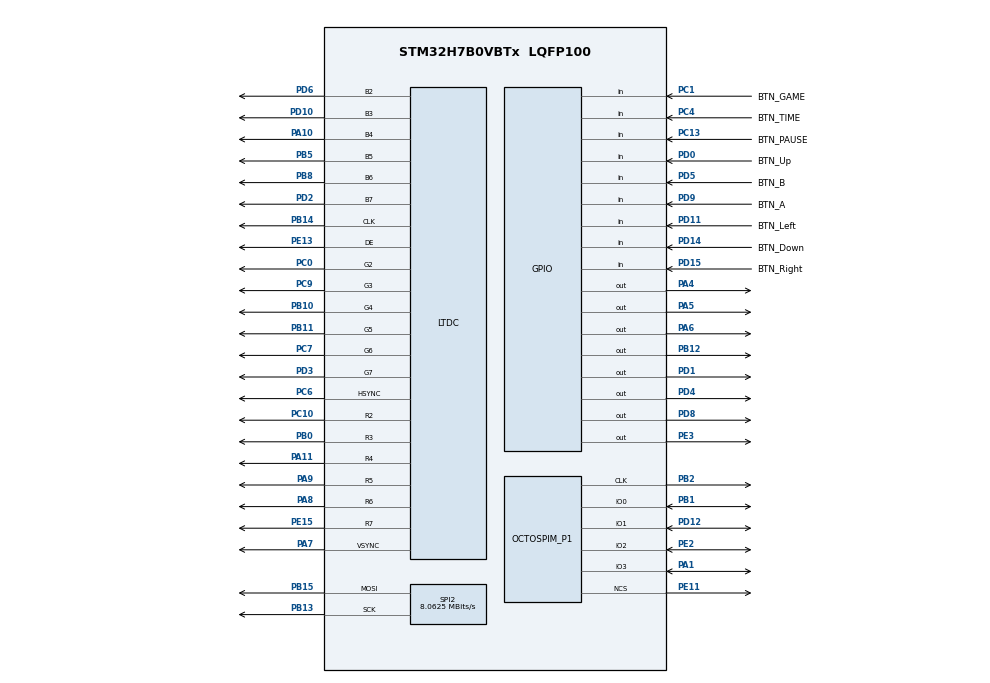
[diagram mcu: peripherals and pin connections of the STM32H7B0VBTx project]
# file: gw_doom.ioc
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SPI2.VirtualType=VM_MASTER
PB10.Mode=RGB666
PB13.Signal=SPI2_SCK
PA5.PinState=GPIO_PIN_SET
OCTOSPI1.ChipSelectBoundary=0
PE2.Mode=OCTOSPI1_IOL_Port1L
PD4.Signal=GPIO_Output
PC7.Signal=LTDC_G6
PB12.PinState=GPIO_PIN_SET
PD0.Signal=GPIO_Input
PD8.Signal=GPIO_Output
PB2.Signal=OCTOSPIM_P1_CLK
RCC.DIVM3=4
PC1.GPIO_PuPd=GPIO_PULLUP
VP_OCTOSPI1_VS_quad.Mode=quad_mode
LTDC.PixelFormat_L0=LTDC_PIXEL_FORMAT_RGB565
PC4.GPIO_Label=BTN_TIME
PB14.Mode=RGB666
PC9.Mode=RGB666
SPI2.CalculateBaudRate=8.0625 MBits/s
PE2.Signal=OCTOSPIM_P1_IO2
PA8.Signal=LTDC_R6
PD14.GPIO_PuPd=GPIO_PULLUP
PE13.Mode=RGB666
PD3.Mode=RGB666
LTDC.HSync=10
Mcu.Package=LQFP100
PB1.Signal=OCTOSPIM_P1_IO0
SPI2.Mode=SPI_MODE_MASTER
RCC.PLL3FRACN=0
PD12.Signal=OCTOSPIM_P1_IO1
PA10.Signal=LTDC_B4
LTDC.VSync=2
RCC.APB4Freq_Value=32000000
PB13.Mode=TX_Only_Simplex_Unidirect_Master
PD9.GPIO_PuPd=GPIO_PULLUP
PD15.Signal=GPIO_Input
PD9.GPIO_Label=BTN_A
PC13.Signal=GPIO_Input
PD3.Signal=LTDC_G7
PC6.Signal=LTDC_HSYNC
PD1.Signal=GPIO_Output
PA6.PinState=GPIO_PIN_SET
PC0.Signal=LTDC_G2
PD6.Mode=RGB666
LTDC.ImageWidth_L0=320
PD10.Signal=LTDC_B3
PD4.PinState=GPIO_PIN_SET
RCC.CDPPRE1=RCC_APB1_DIV2
RCC.CDPPRE2=RCC_APB2_DIV2
PB11.Mode=RGB666
PC6.Mode=RGB666
PA9.Signal=LTDC_R5
RCC.DIVN3=9
PB10.Signal=LTDC_G4
PB14.Signal=LTDC_CLK
PA5.Signal=GPIO_Output
PA1.Mode=OCTOSPI1_IOL_Port1L
PE15.Signal=LTDC_R7
RCC.CDPPRE=RCC_APB3_DIV2
OCTOSPI1.FifoThreshold=4
PA4.Signal=GPIO_Output
OCTOSPI1.MemoryType=HAL_OSPI_MEMTYPE_MACRONIX
PB5.Signal=LTDC_B5
PD12.Mode=OCTOSPI1_IOL_Port1L
PD11.Signal=GPIO_Input
PD1.PinState=GPIO_PIN_RESET
LTDC.Alpha_L0=50
PA11.Signal=LTDC_R4
ProjectManager.HeapSize=0x200
PB1.Mode=OCTOSPI1_IOL_Port1L
PD0.GPIO_PuPd=GPIO_PULLUP
NVIC.PriorityGroup=NVIC_PRIORITYGROUP_4
OCTOSPI1.FreeRunningClock=HAL_OSPI_FREERUNCLK_DISABLE
PB8.Mode=RGB666
PE3.Signal=GPIO_Output
PA8.Mode=RGB666
SPI2.DataSize=SPI_DATASIZE_8BIT
PD2.Signal=LTDC_B7
RCC.DIVR3=26
PB0.Signal=LTDC_R3
PC1.Signal=GPIO_Input
LTDC.Alpha0_L0=128
PE15.Mode=RGB666
Mcu.Family=STM32H7
RCC.CortexFreq_Value=64000000
OCTOSPI1.DeviceSize=20
LTDC.HBP=51
PC10.Signal=LTDC_R2
PD0.GPIO_Label=BTN_Up
PA11.Mode=RGB666
PC13.GPIO_Label=BTN_PAUSE
PB11.Signal=LTDC_G5
PB15.Signal=SPI2_MOSI
LTDC.PCPolarity=LTDC_PCPOLARITY_IIPC
ProjectManager.StackSize=0x400
PD11.GPIO_PuPd=GPIO_PULLUP
OCTOSPI1.ClockPrescaler=1
PE11.Mode=OCTOSPI1_Port1_NCS
RCC.HCLKFreq_Value=64000000
PD11.GPIO_Label=BTN_Left
LTDC.WindowX1_L0=320
PD10.Mode=RGB666
SPI2.BaudRatePrescaler=SPI_BAUDRATEPRESCALER_16
PE3.PinState=GPIO_PIN_SET
LTDC.VBP=6
PE13.Signal=LTDC_DE
OCTOSPI1.ChipSelectHighTime=2
PB5.Mode=RGB666
PC13.GPIO_PuPd=GPIO_PULLUP
LTDC.HFP=12
LTDC.ActiveW=320
RCC.APB3Freq_Value=32000000
PA6.Signal=GPIO_Output
PD5.GPIO_Label=BTN_B
PD15.GPIO_PuPd=GPIO_PULLUP
SPI2.Direction=SPI_DIRECTION_2LINES_TXONLY
PD6.Signal=LTDC_B2
RCC.SRDPPRE=RCC_APB4_DIV2
LTDC.FBStartAdress_L0=0x24000000
OCTOSPI1.ClockMode=HAL_OSPI_CLOCK_MODE_0
LTDC.VFP=8
PD15.GPIO_Label=BTN_Right
LTDC.WindowY1_L0=240
PA7.Mode=RGB666
PA10.Mode=RGB666
PC4.GPIO_PuPd=GPIO_PULLUP
SPI2.NSSPMode=SPI_NSS_PULSE_DISABLE
PC4.Signal=GPIO_Input
PC10.Mode=RGB666
PD9.Signal=GPIO_Input
PD5.Signal=GPIO_Input
PC0.Mode=RGB666
PA9.Mode=RGB666
PA4.PinState=GPIO_PIN_SET
ProjectManager.TargetToolchain=Makefile
LTDC.ActiveH=240
RCC.USBFreq_Value=129000000
PE11.Signal=OCTOSPIM_P1_NCS
PA1.Signal=OCTOSPIM_P1_IO3
PD2.Mode=RGB666
PB0.Mode=RGB666
board=custom
PB15.Mode=TX_Only_Simplex_Unidirect_Master
RCC.APB2Freq_Value=32000000
LTDC.Layers=0
RCC.ADCFreq_Value=129000000
PC1.GPIO_Label=BTN_GAME
PD5.GPIO_PuPd=GPIO_PULLUP
PD14.GPIO_Label=BTN_Down
Mcu.Name=STM32H7B0VBTx
NVIC.OCTOSPI1_IRQn=true\:0\:0\:false\:true\:true\:1\:true\:true
PD14.Signal=GPIO_Input
RCC.SYSCLKFreq_VALUE=64000000
PB2.Mode=O1_P1_CLK
RCC.QSPICLockSelection=RCC_OSPICLKSOURCE_PLL
LTDC.Green_L0=255
PB8.Signal=LTDC_B6
PC9.Signal=LTDC_G3
PC7.Mode=RGB666
RCC.APB1Freq_Value=32000000
PD8.PinState=GPIO_PIN_SET
LTDC.ImageHeight_L0=240
PB12.Signal=GPIO_Output
PA7.Signal=LTDC_VSYNC

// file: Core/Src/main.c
/* USER CODE BEGIN Header */
/**
  ******************************************************************************
  * @file           : main.c
  * @brief          : Main program body
  ******************************************************************************
  * @attention
  *
  * <h2><center>&copy; Copyright (c) 2020 STMicroelectronics.
  * All rights reserved.</center></h2>
  *
  * This software component is licensed by ST under BSD 3-Clause license,
  * the "License"; You may not use this file except in compliance with the
  * License. You may obtain a copy of the License at:
  *                        opensource.org/licenses/BSD-3-Clause
  *
  ******************************************************************************
  */
/* USER CODE END Header */
#include "main.h"

/* USER CODE BEGIN Includes */
#include "buttons.h"
#include "flash.h"
#include "lcd.h"
/* USER CODE END Includes */

LTDC_HandleTypeDef hltdc;

OSPI_HandleTypeDef hospi1;

// SAI_HandleTypeDef hsai_BlockA1;

SPI_HandleTypeDef hspi2;

void SystemClock_Config(void);
static void MX_GPIO_Init(void);
static void MX_LTDC_Init(void);
static void MX_SPI2_Init(void);
static void MX_OCTOSPI1_Init(void);
// static void MX_SAI1_Init(void);
// static void MX_NVIC_Init(void);

int main(void)
{

  /* MCU Configuration--------------------------------------------------------*/

  /* Reset of all peripherals, Initializes the Flash interface and the Systick. */
  HAL_Init();

  /* Configure the system clock */
  SystemClock_Config();

  /* Initialize all configured peripherals */
  MX_GPIO_Init();
  MX_LTDC_Init();
  MX_SPI2_Init();
  MX_OCTOSPI1_Init();
  // MX_SAI1_Init();

  /* Initialize interrupts */
  // MX_NVIC_Init();
  /* USER CODE BEGIN 2 */

  lcd_init(&hspi2, &hltdc);
  memset(framebuffer, 0x00, 320*240*2);

  /* USER CODE END 2 */

  /* Infinite loop */
  /* USER CODE BEGIN WHILE */
  flash_memory_map(&hospi1);

  // Sanity check, sometimes this is triggered
  uint32_t add = 0x90000000;
  uint32_t* ptr = (uint32_t*)add;
  if(*ptr == 0x88888888) {
    Error_Handler();
  }

  uint16_t color = 0x0000;
  uint32_t i =0;

  D_DoomMain();

  while (1)
  {
    /* USER CODE END WHILE */

    /* USER CODE BEGIN 3 */

    uint32_t buttons = buttons_get();
    if(buttons & B_Left) {
      color = 0xf000;
    }
    if(buttons & B_Right) {
      color = 0x0f00;
    }
    if(buttons & B_Up) {
      color = 0x00f0;
    }
    if(buttons & B_Down) {

      color = *ptr&0xff;
    }

    for(int x=0; x < 320; x++) {
      for(int y=0; y < 240; y++) {
        // framebuffer[(y*320)+x] = i;
        if(((x + i)/10 % 2 == 0) && (((y + i)/10 % 2 == 0))){
          framebuffer[(y*320)+x] = color;
        } else {
          framebuffer[(y*320)+x] = 0xffff;
        }
      }
    }

    HAL_Delay(20);
    i++;
  }
  /* USER CODE END 3 */
}

void SystemClock_Config(void)
{
  RCC_OscInitTypeDef RCC_OscInitStruct = {0};
  RCC_ClkInitTypeDef RCC_ClkInitStruct = {0};
  RCC_PeriphCLKInitTypeDef PeriphClkInitStruct = {0};

  /** Supply configuration update enable
  */
  HAL_PWREx_ConfigSupply(PWR_LDO_SUPPLY);
  /** Configure the main internal regulator output voltage
  */
  __HAL_PWR_VOLTAGESCALING_CONFIG(PWR_REGULATOR_VOLTAGE_SCALE0);

  while(!__HAL_PWR_GET_FLAG(PWR_FLAG_VOSRDY)) {}
  /** Macro to configure the PLL clock source
  */
  __HAL_RCC_PLL_PLLSOURCE_CONFIG(RCC_PLLSOURCE_HSI);
  /** Initializes the RCC Oscillators according to the specified parameters
  * in the RCC_OscInitTypeDef structure.
  */
  RCC_OscInitStruct.OscillatorType = RCC_OSCILLATORTYPE_HSI;
  RCC_OscInitStruct.HSIState = RCC_HSI_DIV1;
  RCC_OscInitStruct.HSICalibrationValue = RCC_HSICALIBRATION_DEFAULT;
  RCC_OscInitStruct.PLL.PLLState = RCC_PLL_ON;
  RCC_OscInitStruct.PLL.PLLSource = RCC_PLLSOURCE_HSI;
  RCC_OscInitStruct.PLL.PLLM = 16;
  RCC_OscInitStruct.PLL.PLLN = 140;
  RCC_OscInitStruct.PLL.PLLP = 2;
  RCC_OscInitStruct.PLL.PLLQ = 2;
  RCC_OscInitStruct.PLL.PLLR = 2;
  RCC_OscInitStruct.PLL.PLLRGE = RCC_PLL1VCIRANGE_2;
  RCC_OscInitStruct.PLL.PLLVCOSEL = RCC_PLL1VCOWIDE;
  RCC_OscInitStruct.PLL.PLLFRACN = 0;
  if (HAL_RCC_OscConfig(&RCC_OscInitStruct) != HAL_OK)
  {
    Error_Handler();
  }
  /** Initializes the CPU, AHB and APB buses clocks
  */
  RCC_ClkInitStruct.ClockType = RCC_CLOCKTYPE_HCLK|RCC_CLOCKTYPE_SYSCLK
                              |RCC_CLOCKTYPE_PCLK1|RCC_CLOCKTYPE_PCLK2
                              |RCC_CLOCKTYPE_D3PCLK1|RCC_CLOCKTYPE_D1PCLK1;
  RCC_ClkInitStruct.SYSCLKSource = RCC_SYSCLKSOURCE_PLLCLK;
  RCC_ClkInitStruct.SYSCLKDivider = RCC_SYSCLK_DIV1;
  RCC_ClkInitStruct.AHBCLKDivider = RCC_HCLK_DIV1;
  RCC_ClkInitStruct.APB3CLKDivider = RCC_APB3_DIV2;
  RCC_ClkInitStruct.APB1CLKDivider = RCC_APB1_DIV2;
  RCC_ClkInitStruct.APB2CLKDivider = RCC_APB2_DIV2;
  RCC_ClkInitStruct.APB4CLKDivider = RCC_APB4_DIV2;

  if (HAL_RCC_ClockConfig(&RCC_ClkInitStruct, FLASH_LATENCY_7) != HAL_OK)
  {
    Error_Handler();
  }
  PeriphClkInitStruct.PeriphClockSelection = RCC_PERIPHCLK_LTDC|RCC_PERIPHCLK_SPI2
                              |RCC_PERIPHCLK_OSPI|RCC_PERIPHCLK_CKPER;
  PeriphClkInitStruct.PLL3.PLL3M = 4;
  PeriphClkInitStruct.PLL3.PLL3N = 9;
  PeriphClkInitStruct.PLL3.PLL3P = 2;
  PeriphClkInitStruct.PLL3.PLL3Q = 2;
  PeriphClkInitStruct.PLL3.PLL3R = 24;
  PeriphClkInitStruct.PLL3.PLL3RGE = RCC_PLL3VCIRANGE_3;
  PeriphClkInitStruct.PLL3.PLL3VCOSEL = RCC_PLL3VCOWIDE;
  PeriphClkInitStruct.PLL3.PLL3FRACN = 0;
  PeriphClkInitStruct.OspiClockSelection = RCC_OSPICLKSOURCE_CLKP;
  PeriphClkInitStruct.CkperClockSelection = RCC_CLKPSOURCE_HSI;
  PeriphClkInitStruct.Spi123ClockSelection = RCC_SPI123CLKSOURCE_CLKP;
  if (HAL_RCCEx_PeriphCLKConfig(&PeriphClkInitStruct) != HAL_OK)
  {
    Error_Handler();
  }
}

/**
  * @brief NVIC Configuration.
  * @retval None
  */
static void MX_NVIC_Init(void)
{
  /* OCTOSPI1_IRQn interrupt configuration */
  HAL_NVIC_SetPriority(OCTOSPI1_IRQn, 0, 0);
  HAL_NVIC_EnableIRQ(OCTOSPI1_IRQn);
}

static void MX_LTDC_Init(void)
{

  LTDC_LayerCfgTypeDef pLayerCfg = {0};
  LTDC_LayerCfgTypeDef pLayerCfg1 = {0};

  hltdc.Instance = LTDC;
  hltdc.Init.HSPolarity = LTDC_HSPOLARITY_AL;
  hltdc.Init.VSPolarity = LTDC_VSPOLARITY_AL;
  hltdc.Init.DEPolarity = LTDC_DEPOLARITY_AL;
  hltdc.Init.PCPolarity = LTDC_PCPOLARITY_IIPC;
  hltdc.Init.HorizontalSync = 9;
  hltdc.Init.VerticalSync = 1;
  hltdc.Init.AccumulatedHBP = 60;
  hltdc.Init.AccumulatedVBP = 7;
  hltdc.Init.AccumulatedActiveW = 380;
  hltdc.Init.AccumulatedActiveH = 247;
  hltdc.Init.TotalWidth = 392;
  hltdc.Init.TotalHeigh = 255;
  hltdc.Init.Backcolor.Blue = 0;
  hltdc.Init.Backcolor.Green = 0;
  hltdc.Init.Backcolor.Red = 0;
  if (HAL_LTDC_Init(&hltdc) != HAL_OK)
  {
    Error_Handler();
  }
  pLayerCfg.WindowX0 = 0;
  pLayerCfg.WindowX1 = 320;
  pLayerCfg.WindowY0 = 0;
  pLayerCfg.WindowY1 = 240;
  pLayerCfg.PixelFormat = LTDC_PIXEL_FORMAT_RGB565;
  pLayerCfg.Alpha = 255;
  pLayerCfg.Alpha0 = 255;
  pLayerCfg.BlendingFactor1 = LTDC_BLENDING_FACTOR1_CA;
  pLayerCfg.BlendingFactor2 = LTDC_BLENDING_FACTOR2_CA;
  pLayerCfg.FBStartAdress = 0x24000000;
  pLayerCfg.ImageWidth = 320;
  pLayerCfg.ImageHeight = 240;
  pLayerCfg.Backcolor.Blue = 0;
  pLayerCfg.Backcolor.Green = 255;
  pLayerCfg.Backcolor.Red = 0;
  if (HAL_LTDC_ConfigLayer(&hltdc, &pLayerCfg, 0) != HAL_OK)
  {
    Error_Handler();
  }
  pLayerCfg1.WindowX0 = 0;
  pLayerCfg1.WindowX1 = 0;
  pLayerCfg1.WindowY0 = 0;
  pLayerCfg1.WindowY1 = 0;
  pLayerCfg1.Alpha = 0;
  pLayerCfg1.Alpha0 = 0;
  pLayerCfg1.BlendingFactor1 = LTDC_BLENDING_FACTOR1_CA;
  pLayerCfg1.BlendingFactor2 = LTDC_BLENDING_FACTOR2_CA;
  pLayerCfg1.FBStartAdress = GFXMMU_VIRTUAL_BUFFER0_BASE;
  pLayerCfg1.ImageWidth = 0;
  pLayerCfg1.ImageHeight = 0;
  pLayerCfg1.Backcolor.Blue = 0;
  pLayerCfg1.Backcolor.Green = 0;
  pLayerCfg1.Backcolor.Red = 0;
  if (HAL_LTDC_ConfigLayer(&hltdc, &pLayerCfg1, 1) != HAL_OK)
  {
    Error_Handler();
  }

}

static void MX_OCTOSPI1_Init(void)
{

  OSPIM_CfgTypeDef sOspiManagerCfg = {0};

  /* OCTOSPI1 parameter configuration*/
  hospi1.Instance = OCTOSPI1;
  hospi1.Init.FifoThreshold = 4;
  hospi1.Init.DualQuad = HAL_OSPI_DUALQUAD_DISABLE;
  hospi1.Init.MemoryType = HAL_OSPI_MEMTYPE_MACRONIX;
  hospi1.Init.DeviceSize = 20;
  hospi1.Init.ChipSelectHighTime = 2;
  hospi1.Init.FreeRunningClock = HAL_OSPI_FREERUNCLK_DISABLE;
  hospi1.Init.ClockMode = HAL_OSPI_CLOCK_MODE_0;
  hospi1.Init.WrapSize = HAL_OSPI_WRAP_NOT_SUPPORTED;
  hospi1.Init.ClockPrescaler = 1;
  hospi1.Init.SampleShifting = HAL_OSPI_SAMPLE_SHIFTING_NONE;
  hospi1.Init.DelayHoldQuarterCycle = HAL_OSPI_DHQC_DISABLE;
  hospi1.Init.ChipSelectBoundary = 0;
  hospi1.Init.ClkChipSelectHighTime = 0;
  hospi1.Init.DelayBlockBypass = HAL_OSPI_DELAY_BLOCK_BYPASSED;
  hospi1.Init.MaxTran = 0;
  hospi1.Init.Refresh = 0;
  if (HAL_OSPI_Init(&hospi1) != HAL_OK)
  {
    Error_Handler();
  }
  sOspiManagerCfg.ClkPort = 1;
  sOspiManagerCfg.NCSPort = 1;
  sOspiManagerCfg.IOLowPort = HAL_OSPIM_IOPORT_1_LOW;
  if (HAL_OSPIM_Config(&hospi1, &sOspiManagerCfg, HAL_OSPI_TIMEOUT_DEFAULT_VALUE) != HAL_OK)
  {
    Error_Handler();
  }

}

static void MX_SPI2_Init(void)
{

  /* SPI2 parameter configuration*/
  hspi2.Instance = SPI2;
  hspi2.Init.Mode = SPI_MODE_MASTER;
  hspi2.Init.Direction = SPI_DIRECTION_2LINES_TXONLY;
  hspi2.Init.DataSize = SPI_DATASIZE_8BIT;
  hspi2.Init.CLKPolarity = SPI_POLARITY_LOW;
  hspi2.Init.CLKPhase = SPI_PHASE_1EDGE;
  hspi2.Init.NSS = SPI_NSS_SOFT;
  hspi2.Init.BaudRatePrescaler = SPI_BAUDRATEPRESCALER_16;
  hspi2.Init.FirstBit = SPI_FIRSTBIT_MSB;
  hspi2.Init.TIMode = SPI_TIMODE_DISABLE;
  hspi2.Init.CRCCalculation = SPI_CRCCALCULATION_DISABLE;
  hspi2.Init.CRCPolynomial = 0x0;
  hspi2.Init.NSSPMode = SPI_NSS_PULSE_DISABLE;
  hspi2.Init.NSSPolarity = SPI_NSS_POLARITY_LOW;
  hspi2.Init.FifoThreshold = SPI_FIFO_THRESHOLD_01DATA;
  hspi2.Init.TxCRCInitializationPattern = SPI_CRC_INITIALIZATION_ALL_ZERO_PATTERN;
  hspi2.Init.RxCRCInitializationPattern = SPI_CRC_INITIALIZATION_ALL_ZERO_PATTERN;
  hspi2.Init.MasterSSIdleness = SPI_MASTER_SS_IDLENESS_00CYCLE;
  hspi2.Init.MasterInterDataIdleness = SPI_MASTER_INTERDATA_IDLENESS_00CYCLE;
  hspi2.Init.MasterReceiverAutoSusp = SPI_MASTER_RX_AUTOSUSP_DISABLE;
  hspi2.Init.MasterKeepIOState = SPI_MASTER_KEEP_IO_STATE_DISABLE;
  hspi2.Init.IOSwap = SPI_IO_SWAP_DISABLE;
  if (HAL_SPI_Init(&hspi2) != HAL_OK)
  {
    Error_Handler();
  }

}

static void MX_GPIO_Init(void)
{
  GPIO_InitTypeDef GPIO_InitStruct = {0};

  /* GPIO Ports Clock Enable */
  __HAL_RCC_GPIOE_CLK_ENABLE();
  __HAL_RCC_GPIOC_CLK_ENABLE();
  __HAL_RCC_GPIOA_CLK_ENABLE();
  __HAL_RCC_GPIOB_CLK_ENABLE();
  __HAL_RCC_GPIOD_CLK_ENABLE();

  /*Configure GPIO pin Output Level */
  // HAL_GPIO_WritePin(GPIO_Speaker_enable_GPIO_Port, GPIO_Speaker_enable_Pin, GPIO_PIN_SET);

  /*Configure GPIO pin Output Level */
  HAL_GPIO_WritePin(GPIOA, GPIO_PIN_4|GPIO_PIN_5|GPIO_PIN_6, GPIO_PIN_SET);

  /*Configure GPIO pin Output Level */
  HAL_GPIO_WritePin(GPIOB, GPIO_PIN_12, GPIO_PIN_SET);

  /*Configure GPIO pin Output Level */
  HAL_GPIO_WritePin(GPIOD, GPIO_PIN_8|GPIO_PIN_4, GPIO_PIN_SET);

  /*Configure GPIO pin Output Level */
  HAL_GPIO_WritePin(GPIOD, GPIO_PIN_1, GPIO_PIN_RESET);

  /*Configure GPIO pin : GPIO_Speaker_enable_Pin */
  // GPIO_InitStruct.Pin = GPIO_Speaker_enable_Pin;
  // GPIO_InitStruct.Mode = GPIO_MODE_OUTPUT_PP;
  // GPIO_InitStruct.Pull = GPIO_NOPULL;
  // GPIO_InitStruct.Speed = GPIO_SPEED_FREQ_LOW;
  // HAL_GPIO_Init(GPIO_Speaker_enable_GPIO_Port, &GPIO_InitStruct);

  /*Configure GPIO pins : BTN_PAUSE_Pin BTN_GAME_Pin BTN_TIME_Pin */
  GPIO_InitStruct.Pin = BTN_PAUSE_Pin|BTN_GAME_Pin|BTN_TIME_Pin;
  GPIO_InitStruct.Mode = GPIO_MODE_INPUT;
  GPIO_InitStruct.Pull = GPIO_PULLUP;
  HAL_GPIO_Init(GPIOC, &GPIO_InitStruct);

  /*Configure GPIO pins : PA4 PA5 PA6 */
  GPIO_InitStruct.Pin = GPIO_PIN_4|GPIO_PIN_5|GPIO_PIN_6;
  GPIO_InitStruct.Mode = GPIO_MODE_OUTPUT_PP;
  GPIO_InitStruct.Pull = GPIO_NOPULL;
  GPIO_InitStruct.Speed = GPIO_SPEED_FREQ_LOW;
  HAL_GPIO_Init(GPIOA, &GPIO_InitStruct);

  /*Configure GPIO pin : PB12 */
  GPIO_InitStruct.Pin = GPIO_PIN_12;
  GPIO_InitStruct.Mode = GPIO_MODE_OUTPUT_PP;
  GPIO_InitStruct.Pull = GPIO_NOPULL;
  GPIO_InitStruct.Speed = GPIO_SPEED_FREQ_LOW;
  HAL_GPIO_Init(GPIOB, &GPIO_InitStruct);

  /*Configure GPIO pins : PD8 PD1 PD4 */
  GPIO_InitStruct.Pin = GPIO_PIN_8|GPIO_PIN_1|GPIO_PIN_4;
  GPIO_InitStruct.Mode = GPIO_MODE_OUTPUT_PP;
  GPIO_InitStruct.Pull = GPIO_NOPULL;
  GPIO_InitStruct.Speed = GPIO_SPEED_FREQ_LOW;
  HAL_GPIO_Init(GPIOD, &GPIO_InitStruct);

  /*Configure GPIO pins : BTN_A_Pin BTN_Left_Pin BTN_Down_Pin BTN_Right_Pin
                           BTN_Up_Pin BTN_B_Pin */
  GPIO_InitStruct.Pin = BTN_A_Pin|BTN_Left_Pin|BTN_Down_Pin|BTN_Right_Pin
                          |BTN_Up_Pin|BTN_B_Pin;
  GPIO_InitStruct.Mode = GPIO_MODE_INPUT;
  GPIO_InitStruct.Pull = GPIO_PULLUP;
  HAL_GPIO_Init(GPIOD, &GPIO_InitStruct);

}

/* USER CODE BEGIN 4 */

void EnableMemMapped(void) {
  // OSPI_RegularCmdTypeDef sCommand;
  OSPI_MemoryMappedTypeDef sMemMappedCfg;

  OSPI_RegularCmdTypeDef sCommand = {
    .Instruction = 0xeb, // 4READ
    .InstructionMode = HAL_OSPI_INSTRUCTION_1_LINE,
    .SIOOMode = HAL_OSPI_SIOO_INST_EVERY_CMD,
    .AlternateBytesMode = HAL_OSPI_ALTERNATE_BYTES_NONE,
    .AddressMode = HAL_OSPI_ADDRESS_4_LINES,
    .OperationType = HAL_OSPI_OPTYPE_READ_CFG,
    .FlashId = 0,
    .InstructionDtrMode = HAL_OSPI_INSTRUCTION_DTR_DISABLE,
    .InstructionSize = HAL_OSPI_INSTRUCTION_8_BITS,
    .AddressDtrMode = HAL_OSPI_ADDRESS_DTR_DISABLE,
    .DataMode = HAL_OSPI_DATA_4_LINES,
    .DataDtrMode = HAL_OSPI_DATA_DTR_DISABLE,
    .DQSMode = HAL_OSPI_DQS_DISABLE,
    .AddressSize = HAL_OSPI_ADDRESS_24_BITS,
    .SIOOMode = HAL_OSPI_SIOO_INST_EVERY_CMD, // HAL_OSPI_SIOO_INST_ONLY_FIRST_CMD
    // .SIOOMode = HAL_OSPI_SIOO_INST_ONLY_FIRST_CMD,
    .DummyCycles = 4,
    // .AlternateBytesSize = 1, //HAL_OSPI_ALTERNATE_BYTES_8_BITS, // ??? firmware uses '1' ??
    .AlternateBytesSize = HAL_OSPI_ALTERNATE_BYTES_8_BITS, // ??? firmware uses '1' ??
    .NbData = 1, // Data length
    .AlternateBytes = 0x00,
  };

  // sCommand.FlashId = HAL_OSPI_FLASH_ID_1;
  // sCommand.InstructionMode = HAL_OSPI_INSTRUCTION_8_LINES;
  // sCommand.InstructionSize = HAL_OSPI_INSTRUCTION_8_BITS;
  // sCommand.InstructionDtrMode = HAL_OSPI_INSTRUCTION_DTR_DISABLE;
  // sCommand.AddressMode = HAL_OSPI_ADDRESS_8_LINES;
  // sCommand.AddressSize = HAL_OSPI_ADDRESS_32_BITS;
  // sCommand.AddressDtrMode = HAL_OSPI_ADDRESS_DTR_ENABLE;
  // sCommand.AlternateBytesMode = HAL_OSPI_ALTERNATE_BYTES_NONE;
  // sCommand.DataMode = HAL_OSPI_DATA_8_LINES;
  // sCommand.DataDtrMode = HAL_OSPI_DATA_DTR_ENABLE;
  // sCommand.DQSMode = HAL_OSPI_DQS_ENABLE;
  // sCommand.SIOOMode = HAL_OSPI_SIOO_INST_EVERY_CMD;
  // sCommand.Address = 0;
  // sCommand.NbData = 1;
  /* Memory-mapped mode configuration for Linear burst write operations */
  // sCommand.OperationType = HAL_OSPI_OPTYPE_WRITE_CFG;
  // sCommand.Instruction = 0x66; /* 4PP / 4 x page program */ // LINEAR_BURST_WRITE;
  // sCommand.DummyCycles = 0; //DUMMY_CLOCK_CYCLES_SRAM_WRITE;
  // if (HAL_OSPI_Command(&hospi1, &sCommand, HAL_OSPI_TIMEOUT_DEFAULT_VALUE) !=
  //     HAL_OK) {
  //   Error_Handler();
  // }
  // HAL_Delay(100);

  //  sCommand.OperationType = HAL_OSPI_OPTYPE_WRITE_CFG;
  // sCommand.Instruction = 0x99; /* 4PP / 4 x page program */ // LINEAR_BURST_WRITE;
  // sCommand.DummyCycles = 0; //DUMMY_CLOCK_CYCLES_SRAM_WRITE;
  // if (HAL_OSPI_Command(&hospi1, &sCommand, HAL_OSPI_TIMEOUT_DEFAULT_VALUE) !=
  //     HAL_OK) {
  //   Error_Handler();
  // }
  // HAL_Delay(100);

  sCommand.OperationType = HAL_OSPI_OPTYPE_WRITE_CFG;
  sCommand.Instruction = 0x38; /* 4PP / 4 x page program */ // LINEAR_BURST_WRITE;
  sCommand.DummyCycles = 0; //DUMMY_CLOCK_CYCLES_SRAM_WRITE;
  if (HAL_OSPI_Command(&hospi1, &sCommand, HAL_OSPI_TIMEOUT_DEFAULT_VALUE) !=
      HAL_OK) {
    Error_Handler();
  }
  /* Memory-mapped mode configuration for Linear burst read operations */
  sCommand.OperationType = HAL_OSPI_OPTYPE_READ_CFG;
  sCommand.Instruction = 0xEB; /* 4READ */  //LINEAR_BURST_READ;
  sCommand.DummyCycles = 8; //DUMMY_CLOCK_CYCLES_SRAM_READ;

  if (HAL_OSPI_Command(&hospi1, &sCommand, HAL_OSPI_TIMEOUT_DEFAULT_VALUE) !=
      HAL_OK) {
    Error_Handler();
  }
  /*Disable timeout counter for memory mapped mode*/
  sMemMappedCfg.TimeOutActivation = HAL_OSPI_TIMEOUT_COUNTER_DISABLE;
  sMemMappedCfg.TimeOutPeriod = 0;
  /*Enable memory mapped mode*/
  if (HAL_OSPI_MemoryMapped(&hospi1, &sMemMappedCfg) != HAL_OK) {
    Error_Handler();
  }
}
/* USER CODE END 4 */

void Error_Handler(void)
{
  /* USER CODE BEGIN Error_Handler_Debug */
  /* User can add his own implementation to report the HAL error return state */
  while(1) {
    // Blink display to indicate failure
    lcd_backlight_off();
    HAL_Delay(500);
    lcd_backlight_on();
    HAL_Delay(500);
  }
  /* USER CODE END Error_Handler_Debug */
}

/************************ (C) COPYRIGHT STMicroelectronics *****END OF FILE****/
